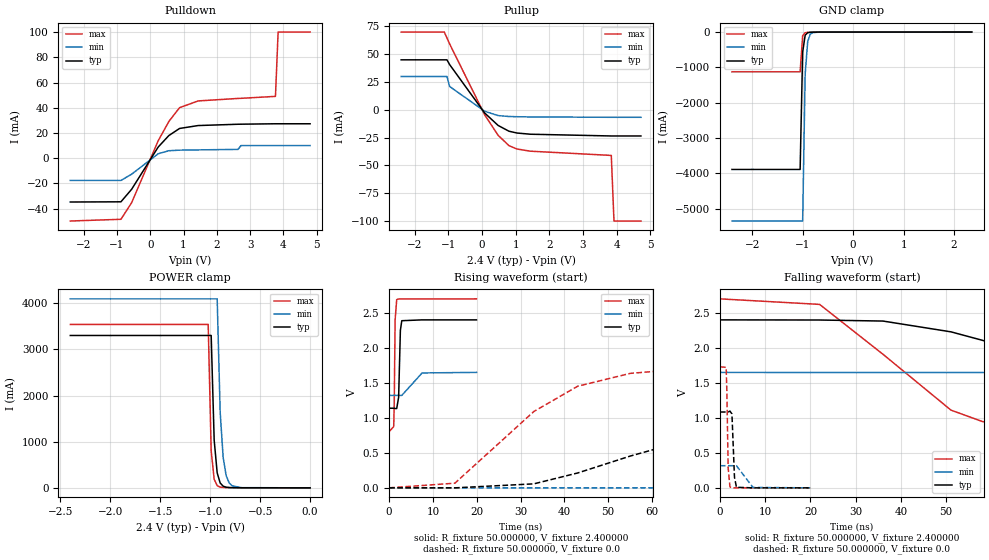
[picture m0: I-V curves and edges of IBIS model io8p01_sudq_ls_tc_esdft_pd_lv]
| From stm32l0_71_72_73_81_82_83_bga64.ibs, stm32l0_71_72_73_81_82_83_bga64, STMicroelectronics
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|   Model io8p01_sudq_ls_tc_esdft_pd_lv
[Model]  io8p01_sudq_ls_tc_esdft_pd_lv
Model_type I/O
Polarity   Non-Inverting
Enable   Active-Low
Vinl =   0.720000V
Vinh =   1.680000V
Vmeas =  1.200000V
Cref =   50.000000pF
Rref =   100.000000M
Vref =   0.0V
C_comp   2.242700pF   2.201100pF   2.288600pF
[Temperature Range]   25.000000   0.105000k   -40.000000
[Pullup Reference]   2.400000V   1.650000V   2.700000V
[Pulldown Reference]   0.0V   0.0V   0.0V
[POWER Clamp Reference]   2.400000V   1.650000V   2.700000V
[GND Clamp Reference]   0.0V   0.0V   0.0V
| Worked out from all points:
|   slope of the pulldown table from 0 to 0.36 V, typ, clamps not added: 28.4 ohm
|   slope of the pullup table from 0 to 0.36 V, typ, clamps not added: 32.2 ohm
|   GND clamp passes 1 mA (typ) near -0.64 V on its own axis
|   POWER clamp passes 1 mA (typ) near -0.63 V on its own axis
|   rising waveform, R_fixture 50.000000, V_fixture 2.400000: 20-80 % time 280ps typ, 629ps min, 186ps max; typ from 1.14 V to 2.4 V
|   rising waveform, R_fixture 50.000000, V_fixture 0.0: 20-80 % time 40.5ns typ, 109ns min, 19.8ns max; typ from 0 V to 1.08 V
|   falling waveform, R_fixture 50.000000, V_fixture 2.400000: 20-80 % time 41.3ns typ, 105ns min, 20.3ns max; typ from 2.4 V to 1.14 V
|   falling waveform, R_fixture 50.000000, V_fixture 0.0: 20-80 % time 354ps typ, 755ps min, 261ps max; typ from 1.08 V to 0 V
[Pulldown]
|Voltage   I(typ)   I(min)   I(max)
-2.4V     -34.71mA   -17.61mA   -49.77mA
-880mV    -34.55mA   -17.61mA   -48.41mA
-560mV    -24.66mA   -12.69mA   -35.31mA
240mV     8.893mA    3.542mA    13.9mA
560mV     17.98mA    5.931mA    29.16mA
880mV     23.58mA    6.389mA    40.03mA
1.44V     25.89mA    6.593mA    45.41mA
2.64V     26.92mA    7mA        47.38mA
2.72V     26.96mA    10mA       47.46mA
3.76V     27.3mA     10mA       49mA
3.84V     27.3mA     10mA       100mA
4.8V      27.3mA     10mA       100mA
[Pullup]
|Voltage   I(typ)   I(min)   I(max)
-2.4V     45mA       30mA       70mA
-1.12V    45mA       30mA       70mA
-1.04V    45mA       30mA       64.7mA
-960mV    40.7mA     21mA       59.3mA
80mV      -2.838mA   -1.261mA   -4.478mA
480mV     -14.04mA   -5.167mA   -22.91mA
800mV     -19.21mA   -5.978mA   -32.18mA
1.04V     -20.85mA   -6.184mA   -35.23mA
1.44V     -21.93mA   -6.373mA   -37.19mA
3.84V     -23.5mA    -6.7mA     -41mA
3.92V     -23.5mA    -6.7mA     -100mA
4.72V     -23.5mA    -6.7mA     -100mA
[GND_clamp]
|Voltage   I(typ)   I(min)   I(max)
-2.4V     -3.892A    -5.353A    -1.127A
-1.05V    -3.892A    -5.353A    -1.127A
-1V       -568.8mA   -5.353A    -105.4mA
-950mV    -88.96mA   -1.19A     -18.04mA
-900mV    -18.16mA   -269.2mA   -8.968mA
-850mV    -6.712mA   -63.46mA   -6.577mA
-800mV    -4.026mA   -16.62mA   -4.866mA
-650mV    -1.055mA   -1.234mA   -1.154mA
2.35V     53.38uA    50.3uA     37.53uA
[POWER_clamp]
|Voltage   I(typ)   I(min)   I(max)
-2.4V     3.303A     4.097A     3.542A
-1.02V    3.303A     4.097A     3.542A
-990mV    3.303A     4.097A     802.4mA
-960mV    1.032A     4.097A     186.5mA
-930mV    325.2mA    4.097A     47.59mA
-900mV    104.8mA    1.637A     15.78mA
-870mV    35.83mA    655.7mA    8.015mA
-840mV    13.93mA    263.9mA    5.668mA
-810mV    6.712mA    107.2mA    4.56mA
-780mV    4.088mA    44.39mA    3.763mA
-690mV    1.741mA    4.361mA    1.91mA
0V        0A         0A         0A
[Ramp]
| variable   typ   min   max
dV/dt_r  0.65004/40.49989n   0.18935/0.10897u   1.03746/19.79506n
dV/dt_f  0.75702/41.28263n   0.19506/0.10553u   1.13766/20.23654n
R_load = 50.000000
[Rising Waveform]
R_fixture= 50.000000
V_fixture= 2.400000
V_fixture_min= 1.650000
V_fixture_max= 2.700000
|time   V(typ)   V(min)   V(max)
0s        1.137V     1.32V      803.3mV
1.041ns   1.137V     1.32V      874.9mV
1.161ns   1.136V     1.32V      1.214V
1.361ns   1.133V     1.32V      2.397V
1.722ns   1.132V     1.32V      2.689V
2.162ns   1.293V     1.32V      2.697V
2.563ns   2.248V     1.32V      2.698V
2.883ns   2.387V     1.32V      2.698V
7.528ns   2.399V     1.641V     2.698V
19.94ns   2.399V     1.649V     2.699V
[Rising Waveform]
R_fixture= 50.000000
V_fixture= 0.0
V_fixture_min= 0.0
V_fixture_max= 0.0
|time   V(typ)   V(min)   V(max)
0s        1.141nV    5.897nV    943.2pV
15.02ns   -165uV     -35.7uV    66.57mV
33.03ns   56.82mV    -35.08uV   1.09V
43.04ns   212.1mV    -35uV      1.451V
55.06ns   454mV      -29.19uV   1.635V
68.07ns   680.9mV    125.5uV    1.701V
95.1ns    950mV      1.593mV    1.727V
139.1ns   1.066V     48.38mV    1.729V
277.3ns   1.083V     273.1mV    1.729V
498.5ns   1.083V     316.1mV    1.729V
[Falling Waveform]
R_fixture= 50.000000
V_fixture= 2.400000
V_fixture_min= 1.650000
V_fixture_max= 2.700000
|time   V(typ)   V(min)   V(max)
0s        2.399V     1.649V     2.699V
22.02ns   2.397V     1.647V     2.62V
36.04ns   2.382V     1.647V     1.907V
51.05ns   2.228V     1.647V     1.11V
58.06ns   2.106V     1.647V     945.7mV
69.07ns   1.881V     1.647V     866.2mV
99.1ns    1.369V     1.647V     815.8mV
133.1ns   1.208V     1.637V     805.8mV
282.3ns   1.138V     1.385V     803.3mV
498.5ns   1.137V     1.32V      803.3mV
[Falling Waveform]
R_fixture= 50.000000
V_fixture= 0.0
V_fixture_min= 0.0
V_fixture_max= 0.0
|time   V(typ)   V(min)   V(max)
0s        1.083V     316.1mV    1.729V
1.361ns   1.083V     316.1mV    1.721V
1.522ns   1.083V     316.1mV    1.37V
1.802ns   1.083V     316.1mV    286.7mV
2.202ns   1.096V     316.1mV    13.46mV
2.643ns   1.055V     316.1mV    459.6uV
3.203ns   151.4mV    315.9mV    -49.52uV
3.644ns   7.723mV    315.6mV    -43.85uV
7.287ns   -3.469uV   5.667mV    -39.83uV
19.94ns   1.141nV    5.897nV    943.2pV
